One B-rep face of a CAD part: STEP entity #627.
In plain terms, the planar face has unit normal (0, 0, -1).
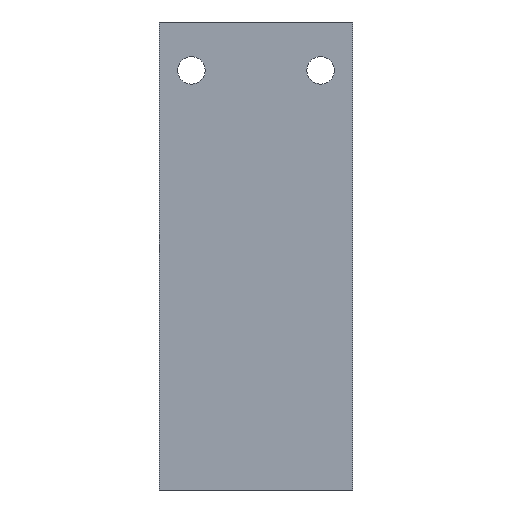
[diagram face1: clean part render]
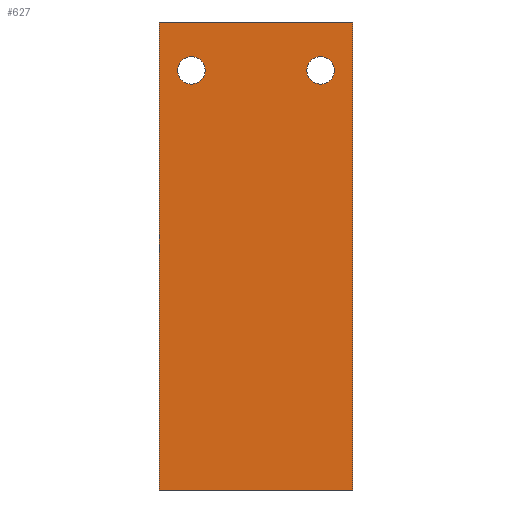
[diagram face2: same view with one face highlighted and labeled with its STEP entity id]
Its self-contained STEP definition (entity closure, numbers rounded to 3 decimals):
#40 = VERTEX_POINT('',#41);
#41 = CARTESIAN_POINT('',(-36.,34.,56.));
#50 = PLANE('',#51);
#51 = AXIS2_PLACEMENT_3D('',#52,#53,#54);
#52 = CARTESIAN_POINT('',(-36.,34.,56.));
#53 = DIRECTION('',(1.,0.,-0.));
#54 = DIRECTION('',(0.,0.,1.));
#62 = PLANE('',#63);
#63 = AXIS2_PLACEMENT_3D('',#64,#65,#66);
#64 = CARTESIAN_POINT('',(-36.,34.,56.));
#65 = DIRECTION('',(-0.,1.,0.));
#66 = DIRECTION('',(0.,0.,1.));
#74 = EDGE_CURVE('',#40,#75,#77,.T.);
#75 = VERTEX_POINT('',#76);
#76 = CARTESIAN_POINT('',(-36.,92.,56.));
#77 = SURFACE_CURVE('',#78,(#82,#89),.PCURVE_S1.);
#78 = LINE('',#79,#80);
#79 = CARTESIAN_POINT('',(-36.,34.,56.));
#80 = VECTOR('',#81,1.);
#81 = DIRECTION('',(-0.,1.,0.));
#82 = PCURVE('',#50,#83);
#83 = DEFINITIONAL_REPRESENTATION('',(#84),#88);
#84 = LINE('',#85,#86);
#85 = CARTESIAN_POINT('',(0.,0.));
#86 = VECTOR('',#87,1.);
#87 = DIRECTION('',(0.,-1.));
#88 = ( GEOMETRIC_REPRESENTATION_CONTEXT(2) 
PARAMETRIC_REPRESENTATION_CONTEXT() REPRESENTATION_CONTEXT('2D SPACE',''
  ) );
#89 = PCURVE('',#90,#95);
#90 = PLANE('',#91);
#91 = AXIS2_PLACEMENT_3D('',#92,#93,#94);
#92 = CARTESIAN_POINT('',(-36.,34.,56.));
#93 = DIRECTION('',(0.,0.,1.));
#94 = DIRECTION('',(1.,0.,-0.));
#95 = DEFINITIONAL_REPRESENTATION('',(#96),#100);
#96 = LINE('',#97,#98);
#97 = CARTESIAN_POINT('',(0.,0.));
#98 = VECTOR('',#99,1.);
#99 = DIRECTION('',(0.,1.));
#100 = ( GEOMETRIC_REPRESENTATION_CONTEXT(2) 
PARAMETRIC_REPRESENTATION_CONTEXT() REPRESENTATION_CONTEXT('2D SPACE',''
  ) );
#118 = PLANE('',#119);
#119 = AXIS2_PLACEMENT_3D('',#120,#121,#122);
#120 = CARTESIAN_POINT('',(-36.,92.,56.));
#121 = DIRECTION('',(-0.,1.,0.));
#122 = DIRECTION('',(0.,0.,1.));
#159 = EDGE_CURVE('',#40,#160,#162,.T.);
#160 = VERTEX_POINT('',#161);
#161 = CARTESIAN_POINT('',(-12.,34.,56.));
#162 = SURFACE_CURVE('',#163,(#167,#174),.PCURVE_S1.);
#163 = LINE('',#164,#165);
#164 = CARTESIAN_POINT('',(-36.,34.,56.));
#165 = VECTOR('',#166,1.);
#166 = DIRECTION('',(1.,0.,-0.));
#167 = PCURVE('',#62,#168);
#168 = DEFINITIONAL_REPRESENTATION('',(#169),#173);
#169 = LINE('',#170,#171);
#170 = CARTESIAN_POINT('',(0.,0.));
#171 = VECTOR('',#172,1.);
#172 = DIRECTION('',(0.,1.));
#173 = ( GEOMETRIC_REPRESENTATION_CONTEXT(2) 
PARAMETRIC_REPRESENTATION_CONTEXT() REPRESENTATION_CONTEXT('2D SPACE',''
  ) );
#174 = PCURVE('',#90,#175);
#175 = DEFINITIONAL_REPRESENTATION('',(#176),#180);
#176 = LINE('',#177,#178);
#177 = CARTESIAN_POINT('',(0.,0.));
#178 = VECTOR('',#179,1.);
#179 = DIRECTION('',(1.,0.));
#180 = ( GEOMETRIC_REPRESENTATION_CONTEXT(2) 
PARAMETRIC_REPRESENTATION_CONTEXT() REPRESENTATION_CONTEXT('2D SPACE',''
  ) );
#220 = PLANE('',#221);
#221 = AXIS2_PLACEMENT_3D('',#222,#223,#224);
#222 = CARTESIAN_POINT('',(-12.,34.,56.));
#223 = DIRECTION('',(1.,0.,-0.));
#224 = DIRECTION('',(0.,0.,1.));
#401 = CYLINDRICAL_SURFACE('',#402,1.7);
#402 = AXIS2_PLACEMENT_3D('',#403,#404,#405);
#403 = CARTESIAN_POINT('',(-32.,40.,54.));
#404 = DIRECTION('',(0.,0.,1.));
#405 = DIRECTION('',(1.,0.,-0.));
#432 = CYLINDRICAL_SURFACE('',#433,1.7);
#433 = AXIS2_PLACEMENT_3D('',#434,#435,#436);
#434 = CARTESIAN_POINT('',(-16.,40.,54.));
#435 = DIRECTION('',(0.,0.,1.));
#436 = DIRECTION('',(1.,0.,-0.));
#523 = VERTEX_POINT('',#524);
#524 = CARTESIAN_POINT('',(-12.,92.,56.));
#545 = EDGE_CURVE('',#523,#75,#546,.T.);
#546 = SURFACE_CURVE('',#547,(#551,#558),.PCURVE_S1.);
#547 = LINE('',#548,#549);
#548 = CARTESIAN_POINT('',(-12.,92.,56.));
#549 = VECTOR('',#550,1.);
#550 = DIRECTION('',(-1.,0.,0.));
#551 = PCURVE('',#118,#552);
#552 = DEFINITIONAL_REPRESENTATION('',(#553),#557);
#553 = LINE('',#554,#555);
#554 = CARTESIAN_POINT('',(0.,24.));
#555 = VECTOR('',#556,1.);
#556 = DIRECTION('',(0.,-1.));
#557 = ( GEOMETRIC_REPRESENTATION_CONTEXT(2) 
PARAMETRIC_REPRESENTATION_CONTEXT() REPRESENTATION_CONTEXT('2D SPACE',''
  ) );
#558 = PCURVE('',#90,#559);
#559 = DEFINITIONAL_REPRESENTATION('',(#560),#564);
#560 = LINE('',#561,#562);
#561 = CARTESIAN_POINT('',(24.,58.));
#562 = VECTOR('',#563,1.);
#563 = DIRECTION('',(-1.,0.));
#564 = ( GEOMETRIC_REPRESENTATION_CONTEXT(2) 
PARAMETRIC_REPRESENTATION_CONTEXT() REPRESENTATION_CONTEXT('2D SPACE',''
  ) );
#627 = ADVANCED_FACE('',(#628,#654,#680),#90,.F.);
#628 = FACE_BOUND('',#629,.F.);
#629 = EDGE_LOOP('',(#630,#631,#632,#653));
#630 = ORIENTED_EDGE('',*,*,#74,.F.);
#631 = ORIENTED_EDGE('',*,*,#159,.T.);
#632 = ORIENTED_EDGE('',*,*,#633,.T.);
#633 = EDGE_CURVE('',#160,#523,#634,.T.);
#634 = SURFACE_CURVE('',#635,(#639,#646),.PCURVE_S1.);
#635 = LINE('',#636,#637);
#636 = CARTESIAN_POINT('',(-12.,34.,56.));
#637 = VECTOR('',#638,1.);
#638 = DIRECTION('',(-0.,1.,0.));
#639 = PCURVE('',#90,#640);
#640 = DEFINITIONAL_REPRESENTATION('',(#641),#645);
#641 = LINE('',#642,#643);
#642 = CARTESIAN_POINT('',(24.,0.));
#643 = VECTOR('',#644,1.);
#644 = DIRECTION('',(0.,1.));
#645 = ( GEOMETRIC_REPRESENTATION_CONTEXT(2) 
PARAMETRIC_REPRESENTATION_CONTEXT() REPRESENTATION_CONTEXT('2D SPACE',''
  ) );
#646 = PCURVE('',#220,#647);
#647 = DEFINITIONAL_REPRESENTATION('',(#648),#652);
#648 = LINE('',#649,#650);
#649 = CARTESIAN_POINT('',(0.,0.));
#650 = VECTOR('',#651,1.);
#651 = DIRECTION('',(0.,-1.));
#652 = ( GEOMETRIC_REPRESENTATION_CONTEXT(2) 
PARAMETRIC_REPRESENTATION_CONTEXT() REPRESENTATION_CONTEXT('2D SPACE',''
  ) );
#653 = ORIENTED_EDGE('',*,*,#545,.T.);
#654 = FACE_BOUND('',#655,.F.);
#655 = EDGE_LOOP('',(#656));
#656 = ORIENTED_EDGE('',*,*,#657,.F.);
#657 = EDGE_CURVE('',#658,#658,#660,.T.);
#658 = VERTEX_POINT('',#659);
#659 = CARTESIAN_POINT('',(-30.3,40.,56.));
#660 = SURFACE_CURVE('',#661,(#666,#673),.PCURVE_S1.);
#661 = CIRCLE('',#662,1.7);
#662 = AXIS2_PLACEMENT_3D('',#663,#664,#665);
#663 = CARTESIAN_POINT('',(-32.,40.,56.));
#664 = DIRECTION('',(0.,0.,1.));
#665 = DIRECTION('',(1.,0.,-0.));
#666 = PCURVE('',#90,#667);
#667 = DEFINITIONAL_REPRESENTATION('',(#668),#672);
#668 = CIRCLE('',#669,1.7);
#669 = AXIS2_PLACEMENT_2D('',#670,#671);
#670 = CARTESIAN_POINT('',(4.,6.));
#671 = DIRECTION('',(1.,0.));
#672 = ( GEOMETRIC_REPRESENTATION_CONTEXT(2) 
PARAMETRIC_REPRESENTATION_CONTEXT() REPRESENTATION_CONTEXT('2D SPACE',''
  ) );
#673 = PCURVE('',#401,#674);
#674 = DEFINITIONAL_REPRESENTATION('',(#675),#679);
#675 = LINE('',#676,#677);
#676 = CARTESIAN_POINT('',(0.,2.));
#677 = VECTOR('',#678,1.);
#678 = DIRECTION('',(1.,0.));
#679 = ( GEOMETRIC_REPRESENTATION_CONTEXT(2) 
PARAMETRIC_REPRESENTATION_CONTEXT() REPRESENTATION_CONTEXT('2D SPACE',''
  ) );
#680 = FACE_BOUND('',#681,.F.);
#681 = EDGE_LOOP('',(#682));
#682 = ORIENTED_EDGE('',*,*,#683,.F.);
#683 = EDGE_CURVE('',#684,#684,#686,.T.);
#684 = VERTEX_POINT('',#685);
#685 = CARTESIAN_POINT('',(-14.3,40.,56.));
#686 = SURFACE_CURVE('',#687,(#692,#699),.PCURVE_S1.);
#687 = CIRCLE('',#688,1.7);
#688 = AXIS2_PLACEMENT_3D('',#689,#690,#691);
#689 = CARTESIAN_POINT('',(-16.,40.,56.));
#690 = DIRECTION('',(0.,0.,1.));
#691 = DIRECTION('',(1.,0.,-0.));
#692 = PCURVE('',#90,#693);
#693 = DEFINITIONAL_REPRESENTATION('',(#694),#698);
#694 = CIRCLE('',#695,1.7);
#695 = AXIS2_PLACEMENT_2D('',#696,#697);
#696 = CARTESIAN_POINT('',(20.,6.));
#697 = DIRECTION('',(1.,0.));
#698 = ( GEOMETRIC_REPRESENTATION_CONTEXT(2) 
PARAMETRIC_REPRESENTATION_CONTEXT() REPRESENTATION_CONTEXT('2D SPACE',''
  ) );
#699 = PCURVE('',#432,#700);
#700 = DEFINITIONAL_REPRESENTATION('',(#701),#705);
#701 = LINE('',#702,#703);
#702 = CARTESIAN_POINT('',(0.,2.));
#703 = VECTOR('',#704,1.);
#704 = DIRECTION('',(1.,0.));
#705 = ( GEOMETRIC_REPRESENTATION_CONTEXT(2) 
PARAMETRIC_REPRESENTATION_CONTEXT() REPRESENTATION_CONTEXT('2D SPACE',''
  ) );
